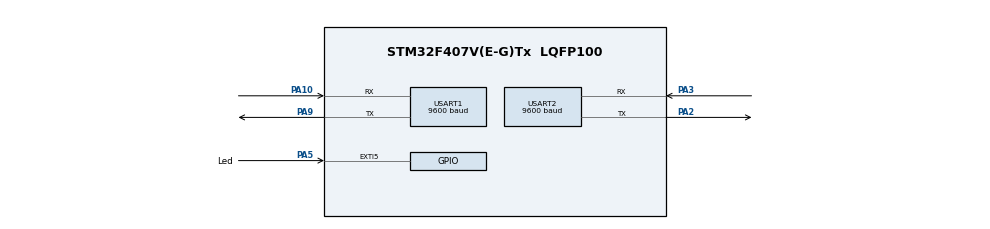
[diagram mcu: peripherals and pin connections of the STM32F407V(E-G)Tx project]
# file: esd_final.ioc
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Mcu.Family=STM32F4
Mcu.Name=STM32F407V(E-G)Tx
Mcu.Package=LQFP100
NVIC.PriorityGroup=NVIC_PRIORITYGROUP_0
PA10.Mode=Asynchronous
PA10.Signal=USART1_RX
PA2.Mode=Asynchronous
PA2.Signal=USART2_TX
PA3.Mode=Asynchronous
PA3.Signal=USART2_RX
PA5.GPIO_Label=Led
PA5.Signal=GPXTI5
PA9.Mode=Asynchronous
PA9.Signal=USART1_TX
PC14-OSC32_IN.Mode=LSE-External-Oscillator
PC14-OSC32_IN.Signal=RCC_OSC32_IN
PC15-OSC32_OUT.Mode=LSE-External-Oscillator
PC15-OSC32_OUT.Signal=RCC_OSC32_OUT
PH0-OSC_IN.Mode=HSE-External-Oscillator
PH0-OSC_IN.Signal=RCC_OSC_IN
PH1-OSC_OUT.Mode=HSE-External-Oscillator
PH1-OSC_OUT.Signal=RCC_OSC_OUT
ProjectManager.HeapSize=0x200
ProjectManager.StackSize=0x400
ProjectManager.TargetToolchain=MDK-ARM V5.32
RCC.48MHZClocksFreq_Value=14285714.285714285
RCC.AHBFreq_Value=25000000
RCC.APB1CLKDivider=RCC_HCLK_DIV4
RCC.APB1Freq_Value=6250000
RCC.APB1TimFreq_Value=12500000
RCC.APB2CLKDivider=RCC_HCLK_DIV2
RCC.APB2Freq_Value=12500000
RCC.APB2TimFreq_Value=25000000
RCC.CortexFreq_Value=25000000
RCC.HCLKFreq_Value=25000000
RCC.HSE_VALUE=8000000
RCC.HSI_VALUE=16000000
RCC.PLLM=8
RCC.PLLN=50
RCC.PLLP=RCC_PLLP_DIV4
RCC.PLLQ=7
RCC.SYSCLKFreq_VALUE=25000000
RCC.SYSCLKSource=RCC_SYSCLKSOURCE_PLLCLK
RCC.VCOOutputFreq_Value=100000000
USART1.BaudRate=9600
USART1.VirtualMode=VM_ASYNC
USART2.BaudRate=9600
USART2.VirtualMode=VM_ASYNC
board=STM32F407G-DISC1

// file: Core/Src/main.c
/* USER CODE BEGIN Header */
/**
  ******************************************************************************
  * @file           : main.c
  * @brief          : Main program body
  ******************************************************************************
  * @attention
  *
  * <h2><center>&copy; Copyright (c) 2021 STMicroelectronics.
  * All rights reserved.</center></h2>
  *
  * This software component is licensed by ST under BSD 3-Clause license,
  * the "License"; You may not use this file except in compliance with the
  * License. You may obtain a copy of the License at:
  *                        opensource.org/licenses/BSD-3-Clause
  *
  ******************************************************************************
  */
/* USER CODE END Header */
#include "main.h"

/* USER CODE BEGIN Includes */
#include <string.h>
#include <stdlib.h>
#include <stdio.h>

/* USER CODE END Includes */

UART_HandleTypeDef huart1;
UART_HandleTypeDef huart2;

/* USER CODE BEGIN PV */

char MsgCMD[20]="AT+CMGF=?\r\n";
char MsgCMD1[20]="AT+CMGF=1\r\n";
char num[50]="AT+CMGS=\"+7980098728\"\r";
char msg[200]="HELLO ENGINEER ARON,THIS MESSAGE IS FROM STM32F446RE.I HAVE BEEN TOLD TO SAY HI BY EDISON,HOW ARE YOU TODAY?";
char Dial_Num[20]="ATD0727880887;\r\n";
char hold[50];
char RX_Buffer[23];

/* USER CODE END PV */

void SystemClock_Config(void);
static void MX_GPIO_Init(void);
static void MX_USART1_UART_Init(void);
static void MX_USART2_UART_Init(void);
/* USER CODE BEGIN PFP */
void GSM_Init(void);
int Send_SMS(void);
void make_phone(void);
/* USER CODE END PFP */

int main(void)
{

  /* MCU Configuration--------------------------------------------------------*/

  /* Reset of all peripherals, Initializes the Flash interface and the Systick. */
  HAL_Init();

  /* Configure the system clock */
  SystemClock_Config();

  /* Initialize all configured peripherals */
  MX_GPIO_Init();
  MX_USART1_UART_Init();
  MX_USART2_UART_Init();
  /* USER CODE BEGIN 2 */
	//GSM_Init();

	HAL_UART_Transmit(&huart1,(uint8_t*)Dial_Num,strlen(Dial_Num),HAL_MAX_DELAY);
  /* USER CODE END 2 */

  /* Infinite loop */
  while (1)
  {

  }
}

void SystemClock_Config(void)
{
  RCC_OscInitTypeDef RCC_OscInitStruct = {0};
  RCC_ClkInitTypeDef RCC_ClkInitStruct = {0};

  /** Configure the main internal regulator output voltage
  */
  __HAL_RCC_PWR_CLK_ENABLE();
  __HAL_PWR_VOLTAGESCALING_CONFIG(PWR_REGULATOR_VOLTAGE_SCALE2);
  /** Initializes the RCC Oscillators according to the specified parameters
  * in the RCC_OscInitTypeDef structure.
  */
  RCC_OscInitStruct.OscillatorType = RCC_OSCILLATORTYPE_HSI;
  RCC_OscInitStruct.HSIState = RCC_HSI_ON;
  RCC_OscInitStruct.HSICalibrationValue = RCC_HSICALIBRATION_DEFAULT;
  RCC_OscInitStruct.PLL.PLLState = RCC_PLL_ON;
  RCC_OscInitStruct.PLL.PLLSource = RCC_PLLSOURCE_HSI;
  RCC_OscInitStruct.PLL.PLLM = 8;
  RCC_OscInitStruct.PLL.PLLN = 64;
  RCC_OscInitStruct.PLL.PLLP = RCC_PLLP_DIV2;
  RCC_OscInitStruct.PLL.PLLQ = 7;
  if (HAL_RCC_OscConfig(&RCC_OscInitStruct) != HAL_OK)
  {
    Error_Handler();
  }
  /** Initializes the CPU, AHB and APB buses clocks
  */
  RCC_ClkInitStruct.ClockType = RCC_CLOCKTYPE_HCLK|RCC_CLOCKTYPE_SYSCLK
                              |RCC_CLOCKTYPE_PCLK1|RCC_CLOCKTYPE_PCLK2;
  RCC_ClkInitStruct.SYSCLKSource = RCC_SYSCLKSOURCE_PLLCLK;
  RCC_ClkInitStruct.AHBCLKDivider = RCC_SYSCLK_DIV4;
  RCC_ClkInitStruct.APB1CLKDivider = RCC_HCLK_DIV2;
  RCC_ClkInitStruct.APB2CLKDivider = RCC_HCLK_DIV1;

  if (HAL_RCC_ClockConfig(&RCC_ClkInitStruct, FLASH_LATENCY_0) != HAL_OK)
  {
    Error_Handler();
  }
}

static void MX_USART1_UART_Init(void)
{

  huart1.Instance = USART1;
  huart1.Init.BaudRate = 9600;
  huart1.Init.WordLength = UART_WORDLENGTH_8B;
  huart1.Init.StopBits = UART_STOPBITS_1;
  huart1.Init.Parity = UART_PARITY_NONE;
  huart1.Init.Mode = UART_MODE_TX_RX;
  huart1.Init.HwFlowCtl = UART_HWCONTROL_NONE;
  huart1.Init.OverSampling = UART_OVERSAMPLING_16;
  if (HAL_UART_Init(&huart1) != HAL_OK)
  {
    Error_Handler();
  }

}

static void MX_USART2_UART_Init(void)
{

  huart2.Instance = USART2;
  huart2.Init.BaudRate = 9600;
  huart2.Init.WordLength = UART_WORDLENGTH_8B;
  huart2.Init.StopBits = UART_STOPBITS_1;
  huart2.Init.Parity = UART_PARITY_NONE;
  huart2.Init.Mode = UART_MODE_TX_RX;
  huart2.Init.HwFlowCtl = UART_HWCONTROL_NONE;
  huart2.Init.OverSampling = UART_OVERSAMPLING_16;
  if (HAL_UART_Init(&huart2) != HAL_OK)
  {
    Error_Handler();
  }

}

static void MX_GPIO_Init(void)
{
  GPIO_InitTypeDef GPIO_InitStruct = {0};

  /* GPIO Ports Clock Enable */
  __HAL_RCC_GPIOC_CLK_ENABLE();
  __HAL_RCC_GPIOH_CLK_ENABLE();
  __HAL_RCC_GPIOA_CLK_ENABLE();

  /*Configure GPIO pin Output Level */
  HAL_GPIO_WritePin(Led_GPIO_Port, Led_Pin, GPIO_PIN_RESET);

  /*Configure GPIO pin : PC13 */
  GPIO_InitStruct.Pin = GPIO_PIN_13;
  GPIO_InitStruct.Mode = GPIO_MODE_IT_FALLING;
  GPIO_InitStruct.Pull = GPIO_PULLUP;
  HAL_GPIO_Init(GPIOC, &GPIO_InitStruct);

  /*Configure GPIO pin : led_Pin */
  GPIO_InitStruct.Pin = Led_Pin;
  GPIO_InitStruct.Mode = GPIO_MODE_OUTPUT_PP;
  GPIO_InitStruct.Pull = GPIO_NOPULL;
  GPIO_InitStruct.Speed = GPIO_SPEED_FREQ_LOW;
  HAL_GPIO_Init(Led_GPIO_Port, &GPIO_InitStruct);

  /* EXTI interrupt init*/
  HAL_NVIC_SetPriority(EXTI15_10_IRQn, 0, 0);
  HAL_NVIC_EnableIRQ(EXTI15_10_IRQn);

}

/* USER CODE BEGIN 4 */

int Send_SMS(void)
{
	int n=26;
  char ch[1];
	ch[0]=n;

	HAL_UART_Transmit(&huart1,(uint8_t*)num,strlen(num),HAL_MAX_DELAY);
	HAL_Delay(1000);

//	HAL_UART_Transmit(&huart1,(uint8_t*)"\r",1,100);

	HAL_UART_Transmit(&huart1,(uint8_t*)msg,strlen(msg),HAL_MAX_DELAY);
	HAL_Delay(100);
	HAL_UART_Transmit(&huart1,(uint8_t*)ch,10,1000);

	return 1;
}

void GSM_Init(void)
{
	HAL_UART_Transmit(&huart1,(uint8_t*)MsgCMD,strlen(MsgCMD),HAL_MAX_DELAY);
	HAL_UART_Receive(&huart1,(uint8_t*)RX_Buffer,10,HAL_MAX_DELAY);
	sprintf(hold,"SMS MODE=%s\r\n\n",RX_Buffer);
	HAL_UART_Transmit(&huart2,(uint8_t*)hold,strlen(hold),HAL_MAX_DELAY);

	///////////////////activate text mode
	HAL_UART_Transmit(&huart1,(uint8_t*)MsgCMD1,strlen(MsgCMD1),HAL_MAX_DELAY);
	HAL_UART_Receive(&huart1,(uint8_t*)RX_Buffer,20,1000);
	sprintf(hold,"\nSMS MODE_NOW=%s\r\n",RX_Buffer);
	HAL_UART_Transmit(&huart2,(uint8_t*)hold,strlen(hold),HAL_MAX_DELAY);
}

/* USER CODE END 4 */

void Error_Handler(void)
{
  __disable_irq();
  while (1)
  {
  }
}

/************************ (C) COPYRIGHT STMicroelectronics *****END OF FILE****/
